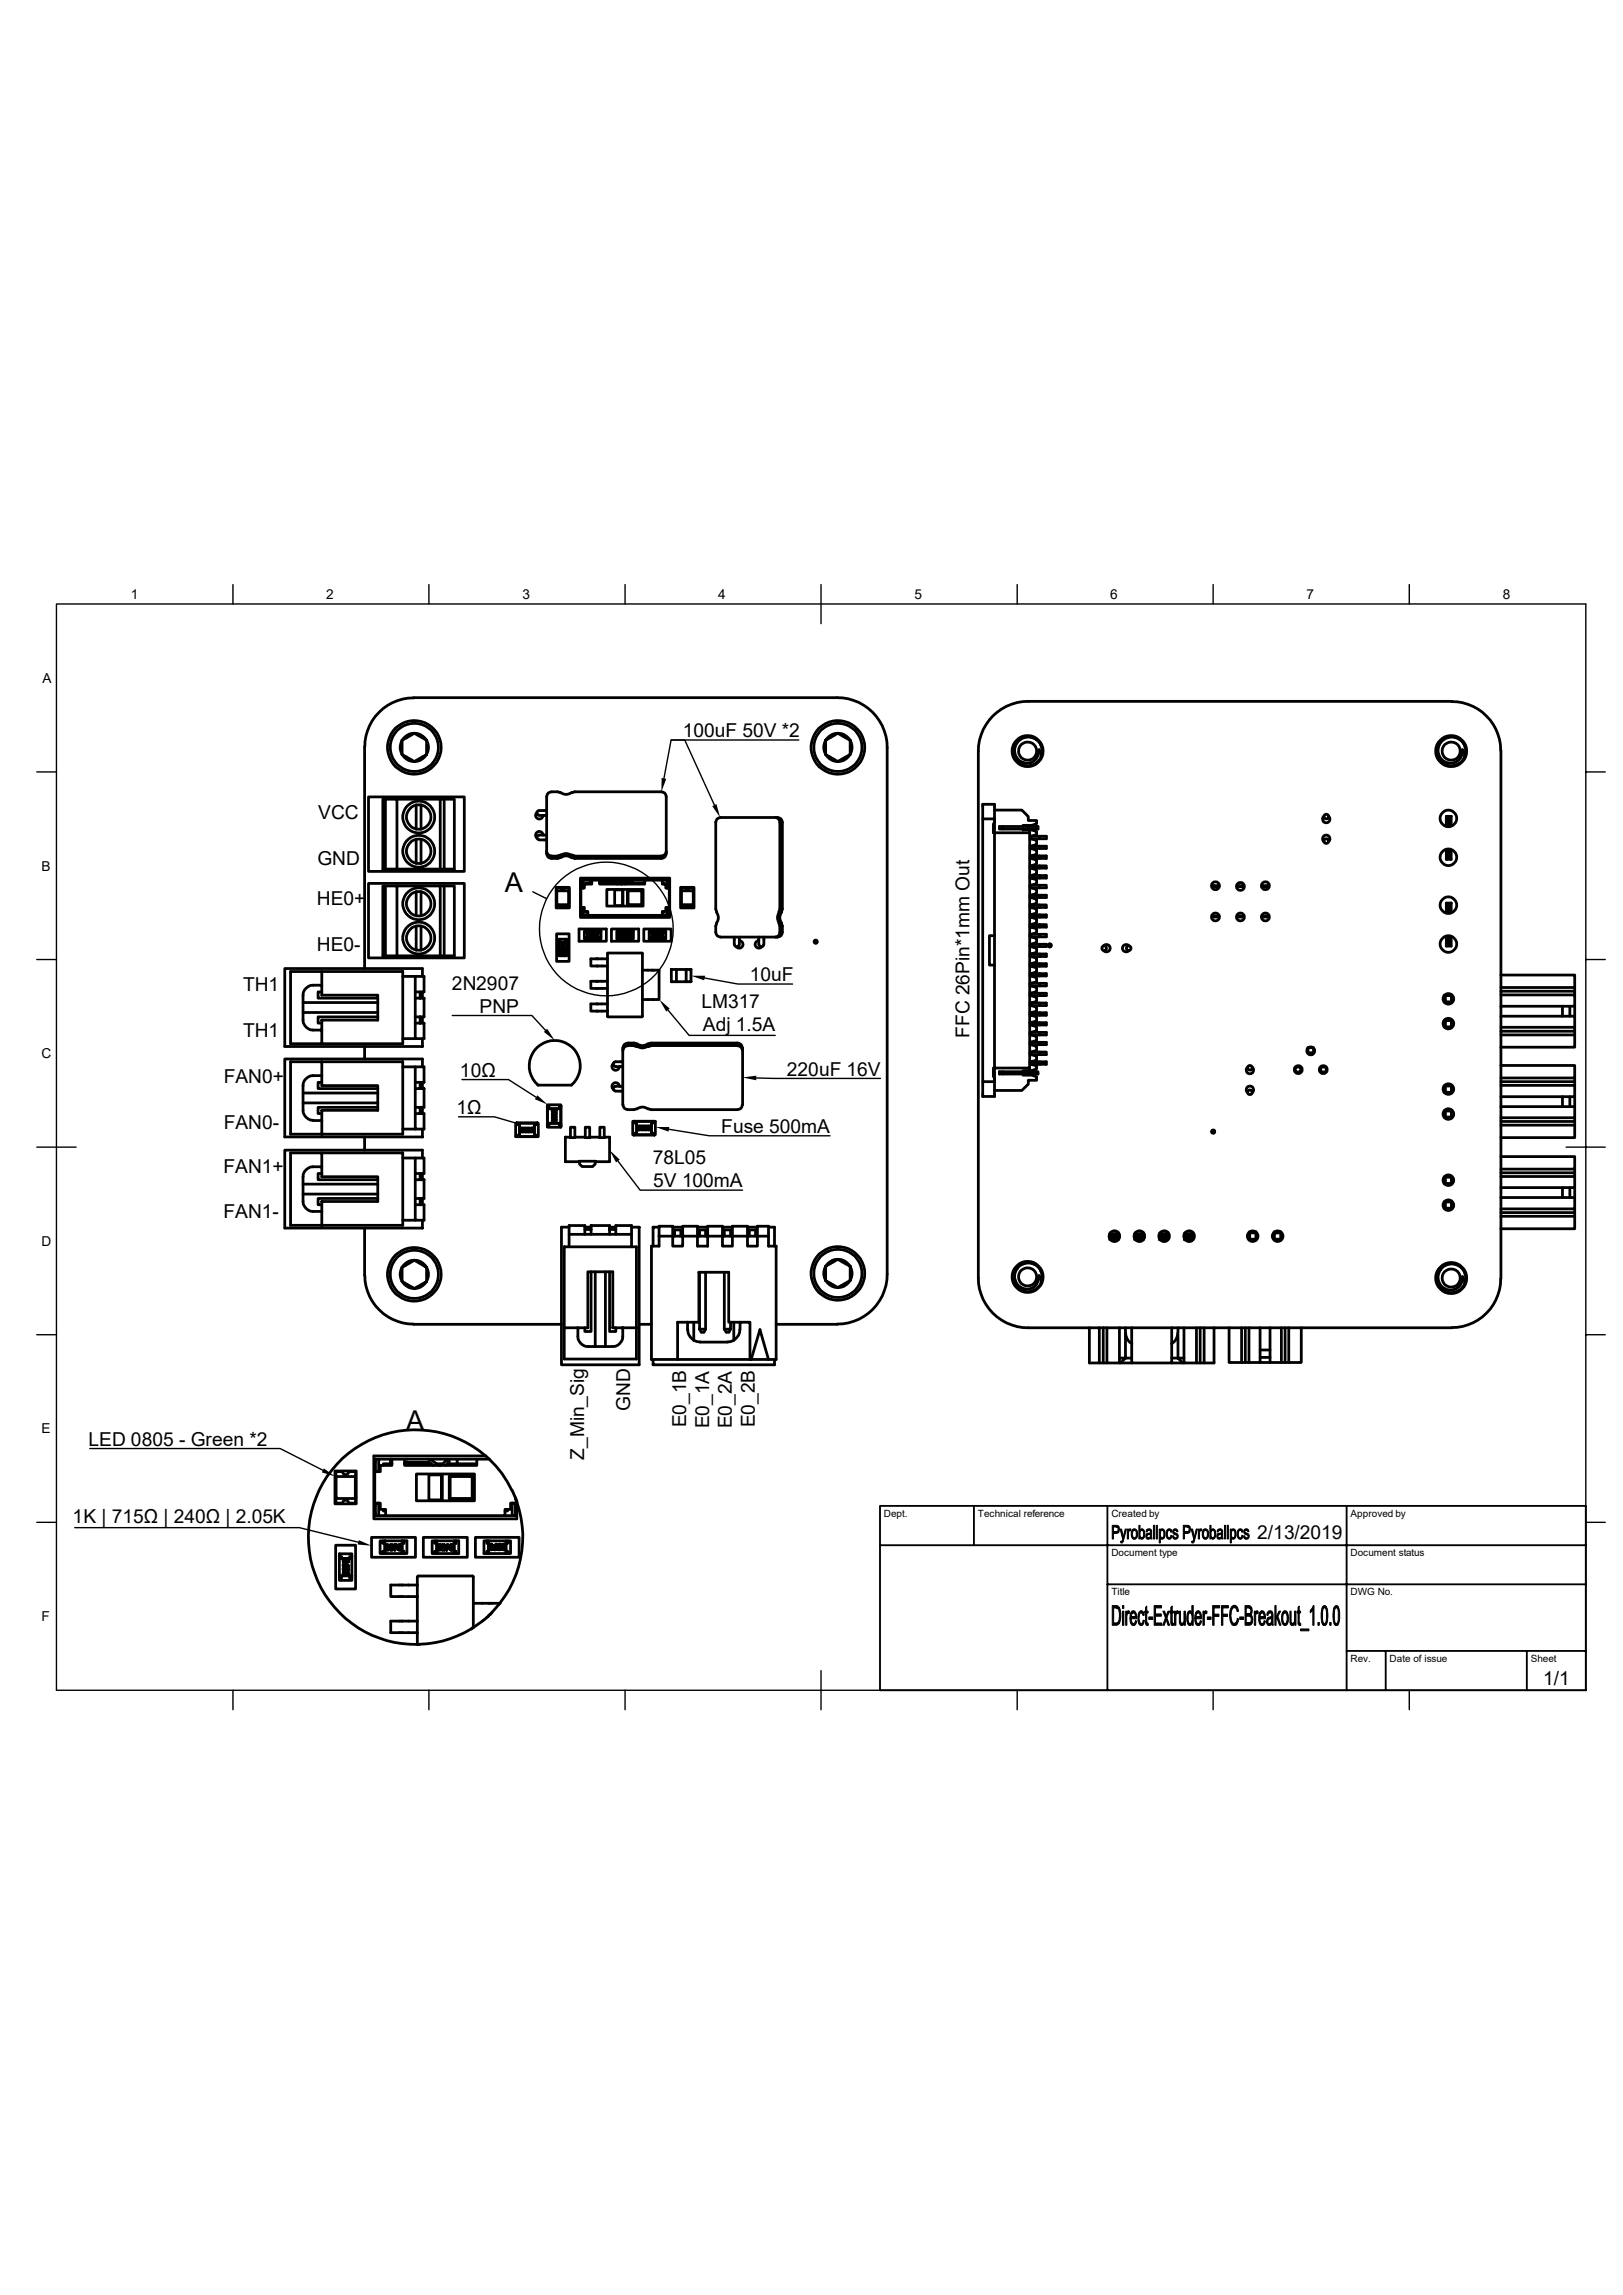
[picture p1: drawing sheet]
<svg xmlns="http://www.w3.org/2000/svg" width="297mm" height="420mm" viewBox="0 0 297 420" stroke-linecap="round" stroke-linejoin="round" font-family="sans-serif">
<defs><g id="words">
<g font-size="5">
<text x="92.4" y="163.2">A</text>
<text x="74.3" y="261.7">A</text>
</g>
<g font-size="3.5">
<text x="124.9" y="134.9">100uF 50V *2</text>
<text x="58.2" y="149.9">VCC</text>
<text x="58.1" y="158.2">GND</text>
<text x="58" y="165.6">HE0+</text>
<text x="58" y="174">HE0-</text>
<text x="137.2" y="179.6">10uF</text>
<text x="44.5" y="181.4">TH1</text>
<text x="82.7" y="181.1">2N2907</text>
<text x="87.8" y="185.3">PNP</text>
<text x="128.4" y="184.5">LM317</text>
<text x="44.5" y="189.8">TH1</text>
<text x="128.6" y="188.7">Adj 1.5A</text>
<text x="177.4" y="189.9" transform="rotate(-90 177.4 189.9)">FFC 26Pin*1mm Out</text>
<text x="84.2" y="197.1">10Ω</text>
<text x="144" y="196.9">220uF 16V</text>
<text x="40.9" y="198.2">FAN0+</text>
<text x="83.5" y="203.9">1Ω</text>
<text x="40.9" y="206.6">FAN0-</text>
<text x="132" y="207.3">Fuse 500mA</text>
<text x="40.9" y="214.6">FAN1+</text>
<text x="119.5" y="213.1">78L05</text>
<text x="119.5" y="217.3">5V 100mA</text>
<text x="40.9" y="223">FAN1-</text>
<text x="115.3" y="258.3" transform="rotate(-90 115.3 258.3)">GND</text>
<text x="125.6" y="261.2" transform="rotate(-90 125.6 261.2)">E0_1B</text>
<text x="129.8" y="261.4" transform="rotate(-90 129.8 261.4)">E0_1A</text>
<text x="133.9" y="261.4" transform="rotate(-90 133.9 261.4)">E0_2A</text>
<text x="138.1" y="261.2" transform="rotate(-90 138.1 261.2)">E0_2B</text>
<text x="16.2" y="264.6">LED 0805 - Green *2</text>
<text x="106.9" y="267.2" transform="rotate(-90 106.9 267.2)">Z_Min_Sig</text>
<text x="13.3" y="278.8">1K | 715Ω | 240Ω | 2.05K</text>
<text x="230.1" y="281.7">2/13/2019</text>
<text x="282.4" y="308.4">1/1</text>
</g>
<g font-size="2.5">
<text x="24" y="109.6">1</text>
<text x="59.7" y="109.6">2</text>
<text x="95.6" y="109.6">3</text>
<text x="131.4" y="109.6">4</text>
<text x="167.3" y="109.6">5</text>
<text x="203.2" y="109.6">6</text>
<text x="239.1" y="109.6">7</text>
<text x="275" y="109.6">8</text>
<text x="7.7" y="125">A</text>
<text x="7.6" y="159.3">B</text>
<text x="7.6" y="193.7">C</text>
<text x="7.6" y="228">D</text>
<text x="7.6" y="262.3">E</text>
<text x="7.6" y="296.6">F</text>
</g>
<g font-size="1.8">
<text x="161.8" y="277.6">Dept.</text>
<text x="178.9" y="277.6">Technical reference</text>
<text x="203.4" y="277.6">Created by</text>
<text x="247.1" y="277.6">Approved by</text>
<text x="203.4" y="284.8">Document type</text>
<text x="247.1" y="284.8">Document status</text>
<text x="203.4" y="292">Title</text>
<text x="247.1" y="292">DWG No.</text>
<text x="247.1" y="304.2">Rev.</text>
<text x="254.3" y="304.2">Date of issue</text>
<text x="280.1" y="304.2">Sheet</text>
</g>
</g></defs>
<g fill="none" stroke="#000" stroke-width=".51">
<path d="M66.7 136.7v40.6M73.6 138.1l2.2 1.3M73.6 135.5v2.6M73.6 138a2.62 2.62 0 0 0 2.2 1.4M73.6 135.5a2.56 2.56 0 0 0 0 2.5M75.7 127.7h77.5a9.1 9.1 0 0 1 9.1 9.1v96.4a9.1 9.1 0 0 1-9.1 9.1M75.7 127.7a9 9 0 0 0-8.9 9M75.8 134.2l-2.2 1.3M75.8 134.2l2.3 1.3M75.8 134.2a2.54 2.54 0 0 1 2.3 1.3M75.8 134.2a2.54 2.54 0 0 0-2.2 1.3M78.1 135.5v2.6"/>
<path d="M78.1 138.1l-2.3 1.3M78.1 138a2.62 2.62 0 0 1-2.3 1.4M78.1 135.5a2.56 2.56 0 0 1 0 2.5M151.1 138.1l2.2 1.3M151.1 135.5v2.6M151.1 138a2.62 2.62 0 0 0 2.2 1.4M151.1 135.5a2.56 2.56 0 0 0 0 2.5M153.3 134.2l-2.2 1.3M153.3 134.2l2.3 1.3M153.3 134.2a2.54 2.54 0 0 1 2.3 1.3M153.3 134.2a2.54 2.54 0 0 0-2.2 1.3M155.6 135.5v2.6"/>
<path d="M155.6 138.1l-2.3 1.3M155.6 138a2.62 2.62 0 0 1-2.3 1.4M155.6 135.5a2.56 2.56 0 0 1 0 2.5M190.1 137.2a2.28 2.28 0 0 1-1.3 2.3l-.5 .2-1-.1a2.4 2.4 0 0 1-1.6-1.9l.1-1.3 .7-.8a2.38 2.38 0 0 1 1.5-.7l1.4 .3 .8 .7 .3 .5-.8-1.1-.8-.4-1-.2-1.2 .4-.9 .8-.4 1.1v1l.4 1 1.1 .9 .7 .2h.9l1.1-.4 .6-.5 .3-.8M190.2 137.2l.3 .7v.5M190.5 136.4l.2 1.4-.2 .6M265.7 128.4h-77.5a9.1 9.1 0 0 0-9.2 9.1v96.3a9.1 9.1 0 0 0 9.2 9.2h77.5a9 9 0 0 0 8.9-9M265.7 128.4a9 9 0 0 1 8.9 8.9M268 136.4l-.5-.7-.7-.6-1-.2-.8 .1-.8 .4-.7 .6-.4 1.1 .2 1a2.19 2.19 0 0 0 1.8 1.6h.5a1.93 1.93 0 0 0 1.4-.7l.2-.2M268 136.4l-.5-.8-.8-.6-1-.3-1 .2-.6 .3-.7 .6-.5 .9-.1 1 .2 .6 .4 .8 .8 .7 .9 .3h.9l.9-.3 .7-.6 .5-.8M268 136.4l.2 1.4-.1 .6M268 136.4h.1"/>
<path d="M268.1 138.4l-.2-.7-.3-.5-.1 1.1-.3 .5M274.7 137.3v96.7M67.4 145.8h17.6v13.7h-17.6zM70.5 146.3h2.1v12.7M72.6 146.3h8v12.7M76.2 147.3v4.5M76.2 153.6v4.4M77 147.3v4.5M77 153.6v4.4M80.6 146.3h.7v12.7M81.3 146.3h1.8v12.7h-13v-12.7h.4v12.7M98.3 148.7a.68 .68 0 0 0 .1 1.1 .68 .68 0 0 0 1-.6"/>
<path d="M98.7 153.7h1.3M98.7 149.2h1.3M99.4 152.8a.68 .68 0 0 0-1-.6 .68 .68 0 0 0-.1 1.2M100 155.8a.87 .87 0 0 0 .9 .8M100 152.8h-1.3a.42 .42 0 0 0-.4 .4 .42 .42 0 0 0 .4 .5M100 148.3h-1.3a.42 .42 0 0 0-.4 .5 .42 .42 0 0 0 .4 .4M100.9 156.7h1.2M102.6 145.1a2.46 2.46 0 0 0-2.3 .1l-.3 .6v10.4a.87 .87 0 0 0 .9 .9h1.2l.5-.2M102.6 145a1.64 1.64 0 0 0 2 0M102.6 157a1.64 1.64 0 0 1 2 0M102.6 156.5a1.83 1.83 0 0 1 2 0M102.6 156.5l-.5 .1"/>
<path d="M104.6 145.1l.6-.2h15.8a.87 .87 0 0 1 .9 .9v10.4a.87 .87 0 0 1-.9 .9h-15.8l-.6-.2M104.6 156.5l.6 .1M105.2 156.7h15.8M121.9 155.8a.87 .87 0 0 1-.9 .8M141.9 149.6a.87 .87 0 0 1 .8 .9v15.9l-.2 .5M179.8 149.9v-2.7h2.2v5.2h-.2v-1.5M181.8 150.9l.2 .6M182 149.9h-2.2v48.1h2.2M182 148.3h5l1.2 1.1v.8h1.5v.5l-.9 .3h-1.6v.3M182 150.3l-.2 .6M182.9 151.3h7v.4h-7zM183.5 151.3v.4"/>
<path d="M187.2 151.7v.2h1.2M188.3 151.3v.4M188.4 151.9l1.3 .3v.5l-1.2 .3v.5l1.2 .3v.7l-1.2 .3v.5l1.2 .3v.7l-1.2 .3v.5l1.2 .3v.7l-1.2 .3v.5l1.2 .3v.7l-1.2 .3v.5l1.2 .3v.7l-1.2 .3v.5l1.2 .3v.7l-1.2 .3v.5l1.2 .3v.7l-1.2 .3v.5l1.2 .3v.7l-1.2 .2v.6l1.2 .3v.7l-1.2 .3v.5l1.2 .3v.7l-1.2 .2v.6l1.2 .2v.8l-1.2 .3v.5l1.2 .3v.7l-1.2 .2v.6l1.2 .2v.8l-1.2 .2v.6l1.2 .2v.7l-1.2 .3v.5l1.2 .3v.8l-1.2 .2v.6l1.2 .2v.7l-1.2 .3v.5l1.2 .3v.8l-1.2 .2v.6l1.2 .2v.7l-1.2 .3v.5l1.2 .3v.7l-1.2 .3v.5l1.2 .3v.7l-1.2 .3v.5l1.2 .3v.7l-1.2 .3v.5l1.2 .3v.7l-1.2 .3v.5l1.2 .3v.7l-1.2 .3v.5l1.2 .3v.5l-1.3 .3M188.4 151.9v43.6h-6.4v-43.1h6.4M188.5 158.5h3v.4h-3M188.5 156.6h3v.5h-1.3M188.5 153h3v.5h-3M188.5 154.9h3v.4h-1.3M189.7 151.3v.4M190.2 154.9v.4h-1.7M190.2 156.6v.5h-1.7M190.2 153v.5"/>
<path d="M190.2 158.5v.4M242.3 154.1a.69 .69 0 0 1-.1-1.1 .69 .69 0 0 1 1 0 .69 .69 0 0 1-.1 1.1M242.3 149.4a.69 .69 0 0 0-.1 1 .69 .69 0 0 0 1 0 .69 .69 0 0 0-.1-1M264.7 151h.9M264.7 149.4h.9M264.7 155.7h.9M265 156.9l.6 .4h-.9zM265 150.6v-.8l-.3-.4v1.6M265 156l-.3-.3v1.6M265 149.8h.2M265.2 156.9v-.9l.4-.3v1.6M265.2 156h-.2v.9"/>
<path d="M265.6 149.4v1.6l-.4-.4M265.6 149.4l-.4 .4v.8h-.2l-.3 .4M58.9 177.8h14.8v13.2h-20.5v-13.2h5.7v2.5M67.4 161.7h17.6v13.6h-17.6zM70.5 162.1h2.1v12.8M72.6 162.1h8v12.8M73.7 178.7h3.9v2.8h-1.6M76 178.7v11.4h1.6v-2.9h-1.6M76.2 163.2v4.4M76.2 169.5v4.4M77 163.2v4.4M77 169.5v4.4"/>
<path d="M77.3 178.7v-1.4h-25.2v14.2h25.2v-1.4M80.6 162.1h.7v12.8M81.3 162.1h1.8v12.8h-13v-12.8h.4v12.8M101.8 162.4h2.4v3.8h-2.4zM101.9 170.9h2.2v5h-2.2zM101.9 163h2.2v2.6h-2.2zM102.3 172.4h1.4v2h-1.4zM102.3 174.6h.2v-.2h.9v.2h.3v.3h-1.4zM102.3 172.2h.2v.2h.9v-.2h.3M102.3 172.4v-.5h1.4v.5M102.3 174.4v.2M102.6 162.5h-.7v3.6h.7"/>
<path d="M102.7 162.5l.2 .4 .4-.2v-.2h.8v3.6h-.8l-.2-.4-.4 .2v.2M102.7 172.6a.29 .29 0 0 1 .4-.1 .29 .29 0 0 1 .2 .3l-.5 .1zM102.7 173.1l.2-.1 .4 .3-.3-.2v.2l-.2 .1-.1-.2zM102.7 174l.2-.1-.2 .2 .1 .2h.2v-.2l.2 .2v-.4l.1 .1v.2l-.2 .1a.24 .24 0 0 1-.3 0 .24 .24 0 0 1-.1-.3zM102.7 173.5l.4-.1 .2 .2v.1l-.1 .2h-.4l-.1-.2zM102.7 173.6l.5-.1 .1 .2-.4 .1zM102.7 172.6h.5l.1 .2h-.5zM102.7 173.1h.1a.15 .15 0 0 1 .2 0 .15 .15 0 0 1 0 .2h-.3zM103.7 174.4v.2M106 170h5v2.3h-5zM106.2 160.7h16.4v7.2h-16.4zM106.3 162.5h.5"/>
<path d="M106.3 166.1h.5M106.4 161.1h.4v1.3h-.4zM106.4 161.3v6M106.7 162.4v.1M106.7 166.1h.1M106.8 166.1h.1v.7h.7v.7h13.6v-.7h.6v-.7h.2M106.8 166.1h-.4v1.4h1.2M106.8 161.1h1.3v.5M106.8 162.4v.1M106.8 166.1v1.4M106.9 170.4h.3v.3h.3v.9h-.3v.2h-.3zM107.2 171.8h.3"/>
<path d="M107.2 170.4h.3M107.3 166.8v.2h.3M107.5 170.4h1.9v1.4h-1.9zM107.5 170.9h.4v.1l-.1-.1h-.2v.2l.1 .1-.1 .2 .3-.1-.1 .2-.3-.1zM108 170.9l.2-.1 .2 .2-.1 .5-.3-.2zM108.1 170.9h.2v.5l-.3-.1zM108.1 161.6h-.8v.2M108.1 161.1h9.9M108.1 161.6h.2M108.3 161.6v.2h-1.4v.7h-.1M108.3 161.1v.5M108.5 170.9a.21 .21 0 0 1 .3 0 .21 .21 0 0 1 0 .3l-.3 .3 .2-.3h-.2z"/>
<path d="M108.5 170.9h.3v.2l-.2 .1zM109 170.9h.1a.3 .3 0 0 1 .3 .2 .3 .3 0 0 1-.3 .4l-.1-.1zM109.1 170.9h.1a.28 .28 0 0 1 .1 .3 .28 .28 0 0 1-.2 .2zM109.4 170.4h.6v1.4h-.4M109.4 171.8h.2M109.6 170.4v.3h-.2v.9h.2v.2M109.7 161.6v.2h8.3v-.7h3.2v.7h.6v.7h.2M109.7 161.4h2.7l.6 .4M109.7 161.6h3M109.7 161.1v.5M111 162.8h6.7v3h-6.7zM111.2 175.5h-3.1v1.3h3.1"/>
<path d="M111.2 179.6h-3.1v1.3h3.1M111.9 170h5v2.3h-5zM112.4 161.1l1.3 .7M112.5 162.9h1.5v2.8h-1.5zM112.9 170.4h.3v.3h.2v.9h-.2v.2h-.3zM113.2 171.8h.2M113.2 170.4h.2M113.4 170.4h2v1.4h-2zM113.4 161.6h.6M113.5 170.9h.3l.1 .1-.2-.1h-.2v.2l.2 .1-.2 .2 .3-.1-.1 .2-.2-.1zM113.8 161.8l.8-.7 .3 .2-.5 .5M113.9 162.9v2.8"/>
<path d="M114 170.9l.2-.1 .1 .2-.1 .5-.3-.2zM114 170.9h.3l-.1 .5-.2-.1zM114.4 170.9l.2-.1 .2 .2-.2 .5h-.1l.1-.3h-.2zM114.5 170.9a.15 .15 0 0 1 .2 0 .15 .15 0 0 1 0 .2l-.1 .1zM114.6 161.6h1.1M114.8 163l.1-.1zM114.8 165.6l.1 .1zM114.8 163v2.6M114.9 163h2.5v2.6h-2.5zM114.9 170.9h.1a.3 .3 0 0 1 .3 .2 .3 .3 0 0 1-.3 .4l-.1-.1zM114.9 162.9h2.5M114.9 165.7h2.5"/>
<path d="M115 170.9l.2 .1v.4l-.3-.1zM115.4 170.4h.5v1.4h-.3M115.4 171.8h.2M115.6 170.4v.3h-.2v.9h.2v.2M115.7 161.1v.5h2.3M117.4 165.7h.1M117.4 162.9l.1 .1zM117.5 163v2.6M117.6 177.5h3v5.4h-3M117.8 170h5v2.3h-5zM119.1 170.4v.3h.2v.9h-.2v.2M119.1 170.4h-.3v1.4h.5"/>
<path d="M119.1 170.4h.2M119.3 170.4h2v1.4h-2zM119.4 170.9l.1-.1 .3 .1-.1 .5h-.3zM119.5 170.9h.2l-.1 .5-.2-.2zM119.9 171.2l.2-.1 .1 .2-.2 .1zM120.1 170.8l-.1 .3h.2l.1 .2-.2 .2-.2-.3zM120.4 170.9h.3l-.1 .5-.2-.1zM120.4 170.8h.2l.2 .2-.2 .5-.2-.2zM120.9 170.8l.3 .1v.1a.21 .21 0 0 1-.1 .4 .21 .21 0 0 1-.3-.2l.1 .2 .3-.1-.2-.2 .2-.2h-.3zM121.2 161.6h.3v.2M121.2 161.1h1.1v1.3h-.3v-1.3M121.3 171.8h.2"/>
<path d="M121.3 170.4h.2M121.5 166.8v.2h-.3M121.5 170.4h.3v1.4h-.3v-.2h-.2v-.9h.2zM122 166.1h.3v1.4h-1.1M122 162.4v.1M122 166.1v1.4M122 162.5h.5M122 166.1h.5M122.1 162.4v.1M122.1 166.1h.1M122.3 161.3h.2v6h-.2M122.9 179.6h.1"/>
<path d="M122.9 177.4v.1M123.7 177.4v.1M123.7 179.6h.1M123.8 177.4h1.8v2.3h-1.8zM123.8 177.4h-.9v2.3h.9M124.5 162.4h2.5v3.8h-2.5zM124.7 163h2.2v2.6h-2.2zM124.7 162.5h.7l.3 .4 .3-.2 .1-.2h.8v3.6h-.8l-.2-.4-.4 .2-.1 .2h-.7zM125.6 177.4h.8v2.3h-.8M125.6 179.6h.1M125.6 177.4v.1M126.4 177.4v.1"/>
<path d="M126.4 179.6h.1M126.9 163.2h.1M131.1 166.9a1.64 1.64 0 0 1 0 2.1M131.1 169a2.46 2.46 0 0 0 .1 2.2l.7 .3h10.4a.87 .87 0 0 0 .9-.9v-1.1l-.2-.5M131.1 166.9l-.1-.5v-15.9a.87 .87 0 0 1 .9-.9h10.4a.87 .87 0 0 1 .9 .9v15.9l-.2 .5M134.4 171.5v1.3M134.4 172.8a.42 .42 0 0 0 .4 .5 .42 .42 0 0 0 .5-.5M135.3 172.2a.68 .68 0 0 1 .6 1 .68 .68 0 0 1-1.2 .1M135.3 171.5v1.3M138.9 172.2a.68 .68 0 0 0-.6 1 .68 .68 0 0 0 1.1 .1M138.9 171.5v1.3M139.8 171.5l-.1 1.3a.42 .42 0 0 1-.4 .5 .42 .42 0 0 1-.4-.5"/>
<path d="M142.5 169a2.46 2.46 0 0 1 0 2.2l-.6 .3M142.6 166.9a1.83 1.83 0 0 0 0 2.1M143 166.9a1.64 1.64 0 0 0 0 2.1M182 171.2h-.9v5.4h.9M188.5 162h3v.5h-3M188.5 165.6h3v.5h-3M188.5 169.2h3v.5h-3M188.5 171h3v.5h-1.3M188.5 160.2h3v.5h-1.3M188.5 163.8h3v.5h-1.3M188.5 167.4h3v.5h-1.3M188.5 172.8h3v.4h-1.3"/>
<path d="M188.5 174.6h3v.4h-3M188.5 176.4h3v.4h-1.3M188.5 178.2h3v.4h-1.3M188.5 180h3v.4h-1.3M190.2 180v.4h-1.7M190.2 178.2v.4h-1.7M190.2 176.4v.4h-1.7M190.2 160.2v.5h-1.7M190.2 163.8v.5h-1.7M190.2 167.4v.5h-1.7M190.2 172.8v.4h-1.7M190.2 171v.5h-1.7"/>
<path d="M190.2 162v.5M190.2 165.6v.5M190.2 169.2v.5M190.2 174.6v.4M201.9 173.1a.69 .69 0 0 1 1-.1 .69 .69 0 0 1 0 1 .69 .69 0 0 1-1-.1M206.6 173.1a.69 .69 0 0 0-1-.1 .69 .69 0 0 0 0 1 .69 .69 0 0 0 1-.1M222.2 167.8h-.2v-.2h.8v.2M222.2 167.6v.2h.9v-.2h-.3M222.2 162.1v.2M222.8 162.1h.3v.2h-1.1v-.2h.8v.2M226.7 167.8h-.3v-.2h.8v.2M226.7 167.6v.2h.8v-.2h-.3"/>
<path d="M226.7 162.1v.2M227.2 162.1h.3v.2h-1.1v-.2h.8v.2M231.2 167.8h-.3v-.2h.8v.2M231.2 167.6v.2h.8v-.2h-.3M231.2 162.1v.2M231.7 162.1h.3v.2h-1.1v-.2h.8v.2M264.7 171.5l.3 .4h.2M264.7 165.3l.3 .3v.9l-.3 .3M264.7 166.8h.9M265 172.8h.2l.4 .3h-.9zM265 171.9v.9M265 165.6h.2"/>
<path d="M265.2 172.8v-.9l.4-.4v1.6M265.6 171.5h-.9v1.6M265.6 165.3h-.9v1.5M265.6 165.3l-.4 .3v.9h-.2M265.6 165.3v1.5l-.4-.3M274.7 178.4h13.5v2.3h-13.5M55.5 185.3h13.6M55.5 183.5h13.6M58.9 181.5h-.7v1.2h10.9M58.9 180.3v1.8h10.2v4.6h-10.2v4.3M58.9 198.1h-.7v1.1h10.9M58.9 196.9v1.8h10.2v4.5h-10.2v4.4"/>
<path d="M58.9 194.3h14.8v13.3h-20.5v-13.3h5.7v2.6M58.9 180.3h-1.6a1.88 1.88 0 0 0-1.8 1.8v4.6a1.88 1.88 0 0 0 1.8 1.8h1.6M58.9 196.9h-1.6a1.88 1.88 0 0 0-1.8 1.8v4.5a1.88 1.88 0 0 0 1.8 1.8M66.7 191.5v2.3M69.1 186.1h-10.9v1.1h.7M73.7 190.1h2.3M73.7 195.2h3.9v2.9h-1.6M76 195.2v11.4h1.6v-2.8h-1.6M76 182.7h1.6v3.4h-1.6M76 199.2h1.6v3.5h-1.6M76.9 181.5v1.2M76.9 186.1v1.1"/>
<path d="M76.9 198.1v1.1M77.3 195.2v-1.4h-25.2v14.3h25.2v-1.5M77.3 181.5v1.2M77.3 186.1v1.1M77.3 198.1v1.1M98.4 198.6h6.2a4.7 4.7 0 0 0 .3-6.7 4.7 4.7 0 0 0-6.8 0 4.7 4.7 0 0 0 .4 6.7M111.2 183.7h-3.1v1.3h3.1M111.3 186.1v-11.7l6.3 .1-.1 11.6M111.3 186.1h6.2M112.2 194.6a.68 .68 0 0 0 .1 1.2 .68 .68 0 0 0 1-.6M112.6 199.7h1.4M112.6 195.2h1.4"/>
<path d="M113.3 198.8a.68 .68 0 0 0-1-.6 .68 .68 0 0 0-.1 1.1M114 198.8h-1.4a.42 .42 0 0 0-.4 .4 .42 .42 0 0 0 .4 .4M114 194.3h-1.4a.42 .42 0 0 0-.4 .4 .42 .42 0 0 0 .4 .5M114 191.8v.3M114 192.2v10M114.9 191.4a.87 .87 0 0 0-.9 .8M114.9 191.3h1.1M116 191.4l.5 .2M116.5 191.1a2.46 2.46 0 0 0-2.2 0l-.3 .7M116.5 191a1.64 1.64 0 0 0 2.1 0M116.5 191.5a1.83 1.83 0 0 0 2.1 0M118.6 191.1l.5-.2h15.9a.87 .87 0 0 1 .8 .9"/>
<path d="M119.1 191.3h15.9M119.1 191.4l-.5 .2M135 191.4a.87 .87 0 0 1 .8 .8M135.9 191.8v.3M135.9 192.2v10M181.8 196.9v-1.4h.2v5.2h-2.2v-2.7M181.8 196.9l.2 .6M182 196.3l-.2 .6M182.9 196.1h7v.5h-7zM183.5 196.1v.5M187.2 196.6v.2h1.6l.9 .3v.6h-1.5v.7l-1.2 1.2h-5M188.3 196.1v.5"/>
<path d="M188.4 195.9h-1.2v.2M188.4 195.5v.4M188.5 192.5h3v.5h-3M188.5 194.3h3v.5h-1.3M188.5 181.8h3v.4h-1.3M188.5 188.9h3v.5h-1.3M188.5 183.6h3v.4h-1.3M188.5 185.3h3v.5h-1.3M188.5 187.2h3v.4h-1.3M188.5 190.8h3v.4h-1.3M189.7 196.1v.5M190.2 190.8v.4h-1.7"/>
<path d="M190.2 188.9v.5h-1.7M190.2 187.2v.4h-1.7M190.2 185.3v.5h-1.7M190.2 183.6v.4h-1.7M190.2 181.8v.4h-1.7M190.2 194.3v.5h-1.7M190.2 192.5v.5M228.3 195.3a.69 .69 0 0 0-.1 1 .69 .69 0 0 0 1 0 .69 .69 0 0 0 0-1M228.3 200a.69 .69 0 0 1-.1-1 .69 .69 0 0 1 1 0 .69 .69 0 0 1 0 1M237 195.3h1v.9h-1zM239.4 191.7h1v1h-1zM239.4 191.8a.72 .72 0 0 0 0 1 .72 .72 0 0 0 1 0 .72 .72 0 0 0 0-1"/>
<path d="M239.4 191.8l.3-.2 .6 .2M241.7 195.3h1v.9h-1zM264.2 182.2h1.4v1.1h-1.1v-1.1M264.2 198.8h1.4v1.1h-1.1v-1.1M264.2 186.8h1.4v1.1h-1.4M264.2 183.3h.3M264.2 199.9h.3M264.5 186.8v1.1M274.7 181.4h13.5v.7M274.7 182.1h13.5v2.1h-13.5M274.7 186h13.5v2h-13.5M274.7 198h13.5v.6"/>
<path d="M274.7 195h13.5v2.3h-13.5M274.7 198.6h13.5v2.1h-13.5M274.7 189.4h13.5M285.9 184.2v1.8M287.3 184.2v1.8M288.2 188v.7h-13.5M288.2 189.4v2.2h-13.5M288.2 180.7v.7M288.2 184.2v1.8M288.2 188.7v.7M288.2 197.3v.7M55.5 201.8h13.6"/>
<path d="M55.5 200h13.6M55.5 218.5h13.6M55.5 216.7h13.6M57.3 205.1h1.6M58.9 214.8h-.7v1.1h10.9M58.9 213.5v1.9h10.2v4.5h-10.2v4.3M58.9 211h14.8v13.2h-20.5v-13.2h5.7v2.5M58.9 213.5h-1.6a1.88 1.88 0 0 0-1.8 1.9v4.5a1.88 1.88 0 0 0 1.8 1.8h1.6M66.7 208.1v2.4M69.1 202.7h-10.9v1.1h.7M69.1 219.3h-10.9v1.2h.7M73.7 211.9h3.9v2.9h-1.6"/>
<path d="M73.7 206.6h2.3M76 211.9v11.4h1.6v-2.8h-1.6M76 215.9h1.6v3.4h-1.6M76.9 202.7v1.1M76.9 214.8v1.1M76.9 219.3v1.2M77.3 211.9v-1.4h-25.2v14.2h25.2v-1.4M77.3 202.7v1.1M77.3 214.8v1.1M77.3 219.3v1.2M94.5 205.6h3.8M94.5 208h3.8"/>
<path d="M94.7 205.6v.2h.4v1.9h-.4v.3M94.7 205.6h-.3v2.4h.7M94.7 205.6h.4M95.1 205.6h2.7v2.4h-2.7zM95.4 206.5l.3-.1 .1 .2v.4l-.1 .2a.4 .4 0 0 1-.4-.3 .4 .4 0 0 1 .1-.4zM95.5 206.5h.2l.1 .2-.1 .4-.3-.2zM96 206.5h.4l-.1 .3 .1 .3-.2 .1-.3-.1 .2-.3zM96 206.5h.3v.1l-.2 .1zM96.1 206.8h.2l.1 .2-.3 .1zM96.5 206.5l.3-.1 .1 .1a.38 .38 0 0 1 .1 .4 .38 .38 0 0 1-.4 .3l-.1-.2zM96.6 206.5h.2l.1 .2-.1 .4-.3-.2zM97.2 206.4h.3l-.3 .1v.2l.3 .1v.3l-.2 .1-.3-.2 .3 .1 .2-.1-.1-.2h-.3z"/>
<path d="M97.8 205.8h.3v-.2h.4v2.4h-.4v-.3h-.3zM97.8 208h.3M97.8 205.6h.3M100.2 202.9h2.4v2.7h-2.4zM100.2 202.2h2.4v.3h-.2v.4h-1.9v-.4h-.3zM100.2 206h.3v-.4h1.9v.4h.2M100.2 202.5v.4M100.2 205.6v.4M100.2 202.4v3.8M101 203.2l.1 .3h.2v-.3h.3l.2 .3-.2 .1 .1-.1-.1-.3-.2 .1v.3l-.4-.1zM101.1 203.8l.5-.1 .2 .3-.1 .2h-.5l-.2-.2zM101.1 204.3h.2a.28 .28 0 0 1 .4 0 .28 .28 0 0 1 .1 .3l-.2 .2-.2-.2-.2 .1-.2-.1z"/>
<path d="M101.1 204.4h.2v.2h-.2zM101.1 205l.5-.1 .1 .2-.4 .1zM101.2 204.9l.4-.1 .2 .2-.1 .3h-.2a.32 .32 0 0 1-.5-.3zM101.2 203.8h.4l.1 .2-.4 .1-.2-.1zM101.5 204.3h.2l-.1 .4-.2-.1zM102.6 205.6v.7h-2.4v-.3M102.6 202.5v.4M102.6 202.4v3.8M104.4 206.3h.8v1.9h-.8zM104.4 208.1h-.9v4.5h2.5M105.2 208.1h1.9M106 212.5h2.9v.5l-.4 .5h-2l-.5-.5z"/>
<path d="M107.1 206.3h.8v1.9h-.8zM107.9 208.1h1.9M108.9 212.6h2.6M109.8 206.3h.8v1.9h-.8zM110.6 208.1h.9v4.5M114 202.2a.87 .87 0 0 0 .9 .9h1.1l.5-.2M115.8 205.2h.4v.3h.3v1.9h-.3v.2h-.4zM116 205.2h3.8M116 207.6h3.8M116.2 205.2h.3M116.2 207.6h.3M116.5 205.2h2.7v2.4h-2.7z"/>
<path d="M116.5 202.9a1.64 1.64 0 0 1 2.1 0M116.8 206.2l.3-.2 .2 .2-.3-.1-.2 .1 .1 .3 .3-.1-.1 .4h-.3l.3-.1v-.2l-.3-.1zM117.4 206.1l.2-.1 .2 .2-.1 .6h-.2l-.2-.2zM117.4 206.2a.27 .27 0 0 1 .4 .1 .27 .27 0 0 1-.1 .4h-.3zM117.9 206.2l.2-.2 .3 .2-.2 .6-.3-.1 .1-.2zM117.9 206.2l.3-.1 .1 .2-.3 .1zM118 206.5h.2l.1 .2h-.3zM118.5 206.2h.3a.34 .34 0 0 1-.2 .5zM118.5 206.1l.2-.1 .2 .2-.1 .6h-.2l-.2-.2zM119.2 205.2h.7v2.4h-.4M119.2 207.6h.3M119.5 205.2v.3h-.3v1.9h.3v.2"/>
<path d="M135.8 202.2a.87 .87 0 0 1-.8 .9h-15.9l-.5-.2M222.2 206.8v.5M264.2 215.4h1.4v1.2h-1.1v-1.2M264.2 203.3h1.4v1.1h-1.4M264.2 220h1.4v1.1h-1.4M264.2 216.6h.3M264.5 203.3v1.1M264.5 220v1.1M274.7 202.5h13.5v2.1h-13.5M274.7 214.6h13.5v.7M274.7 211.7h13.5v2.3h-13.5M274.7 215.3h13.5v2h-13.5"/>
<path d="M274.7 219.2h13.5v2h-13.5M274.7 205.9h13.5M285.9 200.7v1.8M285.9 217.3v1.9M287.3 200.7v1.8M287.3 217.3v1.9M288.2 204.6v.6h-13.5M288.2 205.9v2.3h-13.5M288.2 200.7v1.8M288.2 205.2v.7M288.2 214v.6M288.2 217.3v1.9"/>
<path d="M66.7 224.7v8.7M66.8 233.4a9 9 0 0 0 8.9 8.9M73.6 234.5l2.2 1.3 2.3-1.3M73.6 234.5a2.57 2.57 0 0 0 4.5 0M73.7 223.3h2.3M75.8 230.6l-2.2 1.3v2.6M75.8 230.6l2.3 1.3v2.6M75.8 230.6a2.56 2.56 0 0 1 2.3 3.9M75.8 230.6a2.56 2.56 0 0 0-2.2 3.9M104.1 225.9h11.5v-1.6h-2.9v1.6M104.1 224.6h-1.4v25.2h14.3v-25.2h-1.4M107 225.9v-1.6h-2.9v3.9"/>
<path d="M107 225h1.2M107 224.6h1.2M108.2 232.7v11h-1.2v-.7M108.2 225.9v-1.6h3.3v1.6M108.9 232.7v13.7M110.8 232.7v13.7M111.5 232.7v11h1.2v-.7M111.5 225h1.2M111.5 224.6h1.2M115.6 225.9v2.3M120.6 224.4h2.5v3.7h1.8v-3.7h2.7v3.7h1.9v-3.7h2.7v3.7h1.8v-3.7h2.8v3.7h1.8v-3.7h2v3.7h1.4v20.7h-22.8v-20.7h1.4zM120.6 224.6h-1.1v3.5"/>
<path d="M120.6 226.2h20M123.1 224.6h1.8M123.4 226.2v-1.1h1.2v1.1M127.6 224.6h1.9M128 226.2v-1.1h1.1v1.1M128 232.8v10.4M129.1 232.8v10.4M132.2 224.6h1.8M132.5 226.2v-1.1h1.2v1.1M132.5 232.8v10.4M136.8 224.6h1.8M137.1 226.2v-1.1h1.2v1.1"/>
<path d="M140.6 224.6h1.1v3.5M151.1 231.7v2.7l2.2 1.2M151.1 231.7a2.6 2.6 0 0 0 2.2 3.9M153.3 230.5l-2.2 1.2M153.3 230.5l2.3 1.2M153.3 230.5a2.54 2.54 0 0 1 2.3 1.2M153.3 230.5a2.54 2.54 0 0 0-2.2 1.2M155.6 231.7v2.7l-2.3 1.2M155.6 231.7a2.6 2.6 0 0 1-2.3 3.9M190.1 233.4a2.47 2.47 0 0 1-.5 1.7l-.5 .5a1.99 1.99 0 0 1-1.6 .2l-.6-.1-.5-.4-.6-.8-.1-1.2 .2-.8 .2-.4 .9-.7 .6-.2 .9-.1 1.2 .5 .5 .4 .3 .7-.4-.8-1-.7-.7-.2-.9 .1-1.1 .4-.4 .4-.4 .6-.2 .8v1l.3 .7a2.77 2.77 0 0 0 2 1.4h.7l.8-.3 1-.8 .3-.6v-.3l-.3-.9M190.5 232.7l.2 1.3-.2 .7M203.1 225.8v1.1h1.2"/>
<path d="M203.1 225.8h1.2v1.1M203.1 226.8a.98 .98 0 0 1 .6-1.5 .98 .98 0 0 1 1.2 1 .98 .98 0 0 1-1.4 .8l-.3-.2M203.1 225.8l.4 .3M203.5 226.1h.5v.5h-.5zM203.5 226.6l-.4 .3M204 226.6l.3 .3M204.3 225.8l-.3 .3M204.6 225.5v1.4h-.3M204.6 226.9h.1M207.7 226.8a.98 .98 0 0 1 .5-1.5 .98 .98 0 0 1 1.3 1 .98 .98 0 0 1-1.5 .8l-.2-.2M207.7 225.8l.3 .3M207.7 225.8h1.1"/>
<path d="M207.7 225.8v1.1M208 226.1h.5v.5h-.5zM208 226.6l-.3 .3M208.8 225.8v1.1h-1.1M208.8 225.8l-.3 .3M209.2 225.5v1.4h-.4l-.3-.3M209.2 226.9h.1M212.2 226.8a.98 .98 0 0 1 .6-1.5 .98 .98 0 0 1 1.2 1 .98 .98 0 0 1-1.4 .8l-.3-.2M212.2 225.8l.4 .3M212.2 225.8h1.2M212.2 225.8v1.1M212.6 226.1h.5v.5h-.5z"/>
<path d="M212.6 226.6l-.4 .3M213.4 225.8v1.1h-1.2M213.4 225.8l-.3 .3M213.7 225.5v1.4h-.3l-.3-.3M213.7 226.9h.1M216.8 226.8a.98 .98 0 0 1 .5-1.5 .98 .98 0 0 1 1.3 1 .98 .98 0 0 1-1.5 .8l-.2-.2M216.8 225.8l.3 .3M216.8 225.8v1.1M216.8 225.8h1.1M217.1 226.1h.5v.5h-.5zM217.1 226.6l-.3 .3M217.9 225.8l-.3 .3"/>
<path d="M217.9 225.8v1.1l-.3-.3M218.3 225.5v1.4h-1.5M218.3 226.9h.1M228.7 225.4v1.4h1.1v-1.4M228.7 225.6h1.1M233.2 225.4v.2M234.4 225.4v1.4h-1.2v-1.2h1.2M268 232.9l.2 1.3-.1 .7M268.1 234.9l-.2-.8-.3-.5-.1 1.1-.3 .5M268.1 234.9l-.3 .5-.6 .7-.8 .3-1.2 .2-.9-.3-.9-.8-.5-1.1v-1.1l.5-1 .7-.7 1.2-.4 .9 .1 1.1 .5 .7 1-.4-.6-.6-.5-.9-.3h-1l-.8 .3-.5 .4-.4 .6-.3 .9 .1 .6 .3 .8 .5 .6 .5 .3 .7 .2h.7l.7-.3 .6-.6M274.7 222.6h13.5M288.2 221.2v.7h-13.5"/>
<path d="M288.2 222.6v2.3h-13.5M288.2 221.9v.7M75.7 242.4h27M103.3 243v-14.8h13.2v20.5h-13.2v-5.7h2.4M105.7 243h1.9v-10.3h4.5v10.3h4.4M105.7 243v1.6a1.88 1.88 0 0 0 1.9 1.8h4.5a1.88 1.88 0 0 0 1.9-1.8v-1.6M117 242.4h2.2M119.5 248.8v1h22.2v-1M125.8 242v1.3M125.9 243.3a2.28 2.28 0 0 0 2.2 2.3M127 242v3.3M128 243.2l.3 .6h.5l.3-.6"/>
<path d="M128 243.2h1.1M128.1 245.6h5M132.5 243.2l.4 .6h.5l.3-.6M133.7 242v1.2h-1.2M134.3 242v3.3M135.4 243.3a2.28 2.28 0 0 1-2.3 2.3M135.4 243.3v-1.3h1.8v6.8M135.4 242h-2.1v-9.2h-5.4v9.2h-3.9v6.8M137.5 248.8l1.6-5.5 1.5 5.5M142 242.4h11.2M199.3 243v6.4h3.3M201.2 243v6.4"/>
<path d="M201.9 243v6.4M202.6 243v6.4h2.3v-6.4M204.9 248.5h1.1l-.9 .9M204.9 249.4h2.2M206 244.3v4.2h1.1M206 243v1M206 244a2.36 2.36 0 0 0 1.1 1.9M207.1 243v6.4h7.3v-6.4M214.4 248.5h2.3M214.4 249.4h2.3M215.5 244a2.36 2.36 0 0 1-1.1 1.9M215.6 244.3v4.2l.9 .9"/>
<path d="M215.6 243v1M216.7 243v6.4h2.2v-6.4M219.6 243v6.4M220.3 243v6.4M222.2 243v6.4h-3.3M224.9 243v6.3h2.3M227.2 249.3h.7M227.2 243v6.3M227.9 243v6.3h.7M228.6 243v6.3h2v-6.3M230.6 248.4h1.8M230.6 247.1h1.8"/>
<path d="M230.6 249.3h1.8M232.4 243v6.3h2.1v-6.3M235.2 243v6.3h-.7M235.2 249.3h.6M235.8 243v6.3h2.3v-6.3M61.3 269.2h3.9v6h-3.9zM61.5 270.2h3.5v4h-3.5zM61.5 273.9v1.2h1.2a.55 .55 0 0 1 .5-.6 .55 .55 0 0 1 .6 .6M61.5 273.9h.1M63.8 269.3a.55 .55 0 0 1-.6 .6 .55 .55 0 0 1-.5-.6h-1.2v4.6M63.8 269.3h1.3v4.6M65.1 273.9v1.2h-1.3"/>
<path d="M65.1 273.9h.1M68.6 269.3h.7M68.6 275.1h.7M68.7 267.5h-.1v9.4h.1M69.1 269.3h.1M69.1 275.1v.1M69.3 275.1h.3v1.1h1v1.2h21.8v-1.2h1v-1.1h.3M69.3 275.2h-.6v2.2h1.9M69.3 267h-.6v2.3h.6M69.3 275.1v2.3M70.1 268.2v-.3h1.4v-.9h-2.2v2.3M70.1 276.2v.3h.5"/>
<path d="M71.5 267h12.2M71.5 267.9h.2M71.7 267.9v.3h-2.1v1.1h-.3M71.7 267v.9M74 267.6h4.4l.9 .6M74 267.9h4.9M74 267v.9M76.2 269.7h10.6v5h-10.6zM78.4 267l.5 .2M78.5 269.9h2.4v4.6h-2.4zM78.9 267.2l1.4 1M79.9 267.9h1.1"/>
<path d="M80.8 269.9v4.6M80.8 268.1l-.2 .1M80.9 268.1l.9-1 .5 .4-.8 .7M81.8 267.9h1.9M82.2 274.2h.2v.2zM82.2 270.2v4M82.4 270v.2h-.2zM82.4 270.2h4v4h-4zM82.4 270h4M82.4 274.4h4M86.4 274.2h.1l-.1 .2zM86.4 270l.1 .2h-.1z"/>
<path d="M86.5 270.2v4M87.2 267h-3.5v.9h3.5M88.8 266.4a19.6 19.6 0 0 0-31.2 8.3 19.6 19.6 0 0 0 18.8 26.2v-12.4M88.9 266.4h-20.5v11.6h26.2v-3.2a19.6 19.6 0 0 1-3.1 18.6M88.9 266.4a19.7 19.7 0 0 1 4.8 6.4M89.5 267h-2.3v1.2h-13.2v-.3M92.4 277.4h1.3M92.9 276.2v.3h-.5M93.7 275.2h.6v2.2h-.6zM93.7 272.8l.7 1.6M93.7 275.1v.1M93.7 275.1h.7"/>
<path d="M93.9 275.1v.1M94.4 274.4v2.5h-.1M94.4 274.4l.2 .5M61.4 282.8h3.7v8h-3.7zM62.1 288.8h.4v-.4h1.5v.4h.4v.4h-2.3zM62.1 288.4v-3.2h2.3v3.2M62.1 284.9h.4v.3h1.5v-.3h.4M62.1 288.4h2.3M62.1 288.4v.4M62.8 287l.3-.1h.5a.33 .33 0 0 1 .2 .4 .33 .33 0 0 1-.3 .2l-.6-.1zM62.8 285.5l.8-.2a.35 .35 0 0 1 .2 .4 .35 .35 0 0 1-.4 .3l-.5-.1-.1-.1zM62.9 287.1l.5-.2 .3 .1v.3l-.2 .1h-.4l-.2-.1z"/>
<path d="M62.9 287.7l.2-.1-.2 .3 .1 .3h.2l.1-.3 .3 .3 .1-.3-.1-.2 .2 .3-.1 .2h-.4l-.1 .1h-.3l-.1-.2zM62.9 286.2l.3-.1 .6 .5-.4-.3v.3a.32 .32 0 0 1-.3 .2 .32 .32 0 0 1-.3-.2zM62.9 285.5l.6-.1 .2 .1v.3l-.3 .1h-.4l-.1-.2zM64.4 284.9v-.5h-2.3v.8M64.4 284.9v.3M64.4 288.4v.4M68 281.3h8v3.7h-8zM69.6 282h.5v.4h.3v1.5h-.3v.4h-.5zM70.1 282h4.4v2.3h-.5M70.1 284.3h.3M70.4 282v2.3h3.2v-2.3M70.5 282.8l.5-.1 .2 .1-.1 .2a.23 .23 0 0 0-.3-.2 .23 .23 0 0 0-.1 .3l.2 .1-.2 .2v.1l.1 .1 .4-.1-.2 .2h-.3l-.1-.1 .1-.3-.2-.3z"/>
<path d="M71.3 282.8l.4-.1 .2 .2v.6l-.2 .2h-.2l-.2-.2zM71.5 282.8h.3l.1 .3-.1 .4-.2 .1-.2-.2zM72.1 282.8l.4-.1 .2 .2-.1 .3-.3 .5h-.1l.3-.4-.4-.2zM72.2 282.8h.4l-.1 .4-.3-.1zM72.9 282.8l.4-.1a.72 .72 0 0 1 0 1h-.2l-.2-.2zM73 282.8l.2-.1 .2 .3v.4l-.2 .2-.3-.3zM73.6 284.3h.4M74 282v.4h-.4v1.5h.4v.4M76.4 290.1h-4.9v2.1h4.9M76.4 296.7h-4.9v2.1h4.9M76.4 288.5l.1-.1h10l.1 .1v9.4l2.8-2.2M77.5 281.3h8v3.7h-8z"/>
<path d="M79.1 282h.5v.4h.3v1.5h-.3v.4h-.5zM79.6 284.3h.3M79.6 282h.3M79.9 282h3.2v2.3h-3.2zM80.1 282.8l.4-.1 .2 .2-.4-.2-.2 .2v.2l.3 .1-.3 .2 .1 .2 .4-.1-.2 .2-.3-.2zM80.8 282.8l.2-.1h.2l.2 .1v.6l-.2 .3h-.2l-.2-.2zM81 282.8h.2l.2 .2-.1 .5-.2 .1-.2-.2zM81.7 282.7h.3l.2 .2-.1 .3-.4 .5 .3-.4-.4-.2zM82.4 282.8l.1-.1 .4 .1 .1 .7a.33 .33 0 0 1-.3 .2 .33 .33 0 0 1-.4-.2zM82.5 282.8l.2-.1a.52 .52 0 0 1 .1 .8l-.2 .1a.42 .42 0 0 1-.1-.7zM83.1 282h.8v2.3h-.8M83.4 282v.4h-.3v1.5h.3v.4"/>
<path d="M86.3 298.1a19.4 19.4 0 0 1-9.5 2.8M86.4 298l-.1 .1M86.6 293.4h4.9M86.6 297.8l-.2 .1M87 281.3h8v3.7h-8zM89.1 282v.4h.3v1.5h-.3v.4M89.1 282h-.5v2.3h4.3M89.1 282h.3M89.4 282h3.2v2.3M89.4 282v2.3M89.6 282.7l.3-.1 .3 .2v.6l-.2 .2h-.3l-.2-.2zM89.6 295.5l-.2 .2"/>
<path d="M89.7 282.7h.3l.1 .2v.5l-.2 .1-.3-.1zM90 295.1l-.4 .4M90.8 282.6l-.2 .4h.2a.31 .31 0 0 1 .2 .3 .31 .31 0 0 1-.2 .3h-.3l-.2-.1v-.3zM91.1 282.7l.4-.1 .2 .1v.6l-.2 .3-.4-.1zM91.2 282.8l.4-.1 .1 .6a.25 .25 0 0 1-.3 .2 .25 .25 0 0 1-.3-.2zM91.5 293.4l-1.5 1.7M91.9 282.7l.3-.1 .3 .1-.2 .3 .2 .2v.2l-.2 .2h-.4l-.1-.3 .3 .2h.3v-.3l-.3-.1 .3-.3-.4-.1-.1 .1zM92.6 282h.3M92.9 282h.5v2.3h-.5v-.4h-.3v-1.5h.3zM76.4 300.9h.2M76.6 300.9h.2"/>
<circle cx="75.8" cy="136.8" r="4.4"/>
<circle cx="75.8" cy="136.8" r="4.9"/>
<circle cx="153.3" cy="136.8" r="4.4"/>
<circle cx="153.3" cy="136.8" r="4.9"/>
<circle cx="188" cy="137.5" r="2.84"/>
<circle cx="188" cy="137.5" r="1.65"/>
<circle cx="265.6" cy="137.5" r="2.84"/>
<circle cx="265.6" cy="137.5" r="1.65"/>
<circle cx="76.6" cy="155.8" r="2.25"/>
<circle cx="76.6" cy="149.5" r="2.25"/>
<circle cx="76.6" cy="155.8" r="2.92"/>
<circle cx="76.6" cy="149.5" r="2.92"/>
<circle cx="242.7" cy="153.9" r=".43"/>
<circle cx="242.7" cy="149.4" r=".43"/>
<circle cx="265.1" cy="156.9" r="1.52"/>
<circle cx="265.1" cy="149.8" r="1.52"/>
<circle cx="76.6" cy="165.4" r="2.25"/>
<circle cx="76.6" cy="171.7" r="2.25"/>
<circle cx="76.6" cy="165.4" r="2.92"/>
<circle cx="76.6" cy="171.7" r="2.92"/>
<circle cx="149.3" cy="172.3" r=".3"/>
<circle cx="192.1" cy="173" r=".3"/>
<circle cx="202" cy="173.5" r=".43"/>
<circle cx="206.5" cy="173.5" r=".43"/>
<circle cx="222.4" cy="162.1" r=".72"/>
<circle cx="222.4" cy="167.8" r=".72"/>
<circle cx="227" cy="162.2" r=".72"/>
<circle cx="227" cy="167.8" r=".72"/>
<circle cx="231.6" cy="162.1" r=".72"/>
<circle cx="231.6" cy="167.8" r=".72"/>
<circle cx="265.1" cy="172.8" r="1.52"/>
<circle cx="265.1" cy="165.7" r="1.52"/>
<circle cx="228.7" cy="199.9" r=".43"/>
<circle cx="228.7" cy="195.4" r=".43"/>
<circle cx="237.6" cy="195.7" r=".72"/>
<circle cx="242.1" cy="195.7" r=".72"/>
<circle cx="265" cy="199.3" r=".98"/>
<circle cx="265" cy="182.8" r=".98"/>
<circle cx="265" cy="187.3" r=".98"/>
<circle cx="222" cy="207.1" r=".3"/>
<circle cx="265" cy="203.9" r=".98"/>
<circle cx="265" cy="216" r=".98"/>
<circle cx="75.8" cy="233.2" r="4.4"/>
<circle cx="75.8" cy="233.2" r="4.9"/>
<circle cx="153.3" cy="233" r="4.4"/>
<circle cx="153.3" cy="233" r="4.9"/>
<circle cx="188" cy="233.7" r="2.84"/>
<circle cx="188" cy="233.7" r="1.65"/>
<circle cx="229.2" cy="226.2" r=".98"/>
<circle cx="233.8" cy="226.2" r=".98"/>
<circle cx="265" cy="220.6" r=".98"/>
<circle cx="265.6" cy="233.9" r="2.84"/>
<circle cx="265.6" cy="233.9" r="1.65"/>
<circle cx="63.1" cy="286.4" r=".22"/>
<circle cx="81.9" cy="283" r=".22"/>
<circle cx="90.6" cy="283.3" r=".2"/>
</g>
<g fill="none" stroke="#000" stroke-width=".25">
<path d="M10.3 110.5h279.9v198.8h-279.9zM42.6 107v3.5M78.5 107v3.5M114.4 107v3.5M150.2 107v7.1M186.1 107v3.5M222 107v3.5M257.9 107v3.5M122.8 135.4h2.5l5.4 11.9M146.2 135.4h-23.4l-1.3 7.1M6.7 141.3h3.6M290.2 141.3h3.6"/>
<path d="M6.7 175.6h3.6M97.5 163.2l2.5 1.3M128.9 179l6.1 1.1h10M290.2 175.6h3.6M82.8 185.8h14.5l2.5 2.8M84.5 197.6h8.5l5.1 3.2M122.3 184.9l3.8 4.6h15.8M138.4 197.3l22.7 .1M6.7 209.9h7.2M83.9 204.4h6.6l3.9 1.1M113.1 212.5l4 5.3h18.8M122.4 206.7l7.4 1.2h22.1"/>
<path d="M286.6 209.9h7.2M6.7 244.3h3.6M290.2 244.3h3.6M6.7 278.6h3.6M13.7 279.6h41.1l10.8 2.6M16.4 265.1h34.9l7.8 4M290.2 278.6h3.6M42.6 309.3v3.6M78.5 309.3v3.6M114.4 309.3v3.6M150.2 305.7v7.2M186.1 309.3v3.6"/>
<path d="M222 309.3v3.6M257.9 309.3v3.6"/>
<circle cx="110.9" cy="170" r="12.2"/>
</g>
<path d="M161 275.6h129.2v33.7h-129.2zM178.2 275.6v7.2M202.6 275.6v33.7M246.4 275.6v33.7M161 282.8h129.2M202.6 289.9h87.6M246.4 302.1h43.8M253.6 302.1v7.2M279.4 302.1v7.2" fill="none" stroke="#000" stroke-width=".34"/>
<g fill="#000" stroke="#000" stroke-width=".18">
<path d="M203.5 279.1h.9l.4 .3h-1v.9l.9 .1-.2 .2h-.7v1h-.3z" fill-rule="evenodd"/>
<path d="M204.2 279.4h.6l.1 .6-.2 .4-.9-.1h.5l.3-.1v-.5l-.2-.3z" fill-rule="evenodd"/>
<path d="M205 279.8h.2l.4 1.5-.2 .3z" fill-rule="evenodd"/>
<path d="M205.9 279.8h.2l-.5 2.2-.4 .1 .2-.2z" fill-rule="evenodd"/>
<path d="M206.3 279.8h.2v.3h.2l-.2 .4v1.1h-.2z" fill-rule="evenodd"/>
<path d="M206.6 279.9l.3-.1v.4l-.4-.1z" fill-rule="evenodd"/>
<path d="M207.3 279.9l.4-.1 .4 .4 .1 .9-.5 .6h-.3l-.2-.3h.5l.2-.2v-1l-.3-.2h-.4z" fill-rule="evenodd"/>
<path d="M208.4 279.1h.2v.9h.3l-.3 .4v.7l.2 .3h-.2v.2h-.2z" fill-rule="evenodd"/>
<path d="M208.6 280l.3-.2 .3 .1a1.57 1.57 0 0 1 .2 1.5l-.4 .3-.4-.2 .4-.1a.93 .93 0 0 0 0-1.4z" fill-rule="evenodd"/>
<path d="M209.9 279.9l.5-.1 .3 .2 .1 1.6h-.2v-.2h-.3l.2-.2v-.4l-.7-.1 .2-.1a.35 .35 0 0 0 .4-.1 .35 .35 0 0 0 0-.4l-.6-.1z" fill-rule="evenodd"/>
<path d="M212.3 280h.4z" fill-rule="evenodd"/>
<path d="M212.1 279.8h.2v.3h.3l-.3 .3v.7l.3 .3-.3 .1v.9h-.2z" fill-rule="evenodd"/>
<path d="M212.5 279.8a.57 .57 0 0 1 .7 .6v.7l-.2 .4-.4 .2-.3-.2a.78 .78 0 0 0 .7-.6 .78 .78 0 0 0-.2-.8l-.5-.1z" fill-rule="evenodd"/>
<path d="M213.7 279.8h.4l.3 .2h-.5l-.2 .2-.1 .8 .3 .4h-.3l-.2-.3v-.6z" fill-rule="evenodd"/>
<path d="M214.7 279.9l.6-.1 .3 .5h-.3l-.2-.3h-.4z" fill-rule="evenodd"/>
<path d="M216.5 279.1h.9l.4 .3h-1.1v.9l1 .1-.2 .2h-.8v1h-.2z" fill-rule="evenodd"/>
<path d="M217.2 279.4h.6v.6l-.1 .4-1-.1h.6l.3-.1v-.5l-.2-.3z" fill-rule="evenodd"/>
<path d="M218 279.8h.2l.4 1.5-.2 .3z" fill-rule="evenodd"/>
<path d="M218.9 279.8h.2l-.5 2.2-.4 .1 .2-.2z" fill-rule="evenodd"/>
<path d="M219.3 279.8h.2v.3h.2l-.2 .4v1.1h-.2z" fill-rule="evenodd"/>
<path d="M219.6 279.9l.3-.1v.4l-.4-.1z" fill-rule="evenodd"/>
<path d="M220.3 279.9l.4-.1 .4 .4v.9l-.4 .6h-.3l-.2-.3h.5l.2-.2v-1l-.3-.2h-.4z" fill-rule="evenodd"/>
<path d="M221.4 279.1h.2v.9h.3l-.3 .4v.7l.2 .3h-.2v.2h-.2z" fill-rule="evenodd"/>
<path d="M221.8 279.8l.4 .1a1.57 1.57 0 0 1 .2 1.5l-.4 .3-.4-.2 .4-.1a.93 .93 0 0 0 0-1.4h-.4z" fill-rule="evenodd"/>
<path d="M222.9 279.9l.5-.1 .3 .2 .1 1.6h-.2v-.2h-.3l.2-.2v-.4l-.7-.1 .2-.1a.41 .41 0 0 0 .5-.4l-.2-.2h-.5z" fill-rule="evenodd"/>
<path d="M225.3 280h.4z" fill-rule="evenodd"/>
<path d="M225.1 279.8h.2v.3h.3l-.3 .3v.7l.3 .3-.3 .1v.9h-.2z" fill-rule="evenodd"/>
<path d="M225.3 280l.2-.2a.57 .57 0 0 1 .7 .6v.7l-.2 .4-.4 .2-.3-.2a.78 .78 0 0 0 .7-.6 .78 .78 0 0 0-.2-.8z" fill-rule="evenodd"/>
<path d="M226.5 280l.4-.2 .4 .2h-.4l-.2 .3-.1 .7 .3 .4h-.3l-.2-.3z" fill-rule="evenodd"/>
<path d="M227.7 279.9l.6-.1 .3 .5h-.3l-.2-.3h-.4z" fill-rule="evenodd"/>
<path d="M203.5 293.8l1 .1 .4 .3-1.1 .1v2.7h1.1l-.5 .4h-.9z" fill-rule="evenodd"/>
<path d="M204.2 294.3l.7-.1 .2 1-.2 1.7v.1h-.5l.2-.1a2.61 2.61 0 0 0 .1-2.3l-.2-.3z" fill-rule="evenodd"/>
<path d="M205.1 282.1h.4l-.3 .3h-.1z" fill-rule="evenodd"/>
<path d="M205.4 294.9h.3v2.5h-.3z" fill-rule="evenodd"/>
<path d="M205.4 293.8h.3v.5h-.3z" fill-rule="evenodd"/>
<path d="M206 294.9h.2v.3h.2l-.2 .5v1.7h-.2z" fill-rule="evenodd"/>
<path d="M206.3 294.9l.2-.1 .2 .1-.1 .4-.4-.1z" fill-rule="evenodd"/>
<path d="M206.9 295.1h.5a.65 .65 0 0 0-.4 .8h1v.3h-1l.1 .7 .3 .2h-.4l-.2-.4v-.7z" fill-rule="evenodd"/>
<path d="M207.1 280.1l.5-.1-.1 .1a.99 .99 0 0 0-.2 1.1l.3 .2h-.4l-.1-.2-.1-.7z" fill-rule="evenodd"/>
<path d="M207.1 294.9l.2-.1a.97 .97 0 0 1 .7 1.1h-1h.8l-.1-.4-.2-.4h-.5z" fill-rule="evenodd"/>
<path d="M207 297.1h.6l.2-.5 .2 .1-.1 .2a.53 .53 0 0 1-.7 .5z" fill-rule="evenodd"/>
<path d="M208.4 295l.5-.2 .4 .3a.72 .72 0 0 0-.9 .9l.1 .7 .3 .4h-.4l-.2-.5 .1-1.2z" fill-rule="evenodd"/>
<path d="M208.6 281.4h.4z" fill-rule="evenodd"/>
<path d="M208.4 297.1h.6l.2-.6h.2v.3a.52 .52 0 0 1-.4 .6 .52 .52 0 0 1-.6-.3z" fill-rule="evenodd"/>
<path d="M208.8 295.1h.5l.1 .5-.2 .1-.1-.4z" fill-rule="evenodd"/>
<path d="M209.8 280.1l.4-.1-.2 .2-.1 .2-.2-.1z" fill-rule="evenodd"/>
<path d="M209.8 293.9v1h.3v.3h-.3v1.5l.2 .4h-.4v-1.9h-.1v-.3h.1v-.7z" fill-rule="evenodd"/>
<path d="M209.8 280.8h.7h-.1a.36 .36 0 0 0-.4 .2 .36 .36 0 0 0 .1 .4l.4 .1-.3 .2-.3-.1-.2-.3z" fill-rule="evenodd"/>
<path d="M209.6 297.1h.5v.3a.36 .36 0 0 1-.5-.3z" fill-rule="evenodd"/>
<path d="M210.2 295.9h.7v.5h-.7z" fill-rule="evenodd"/>
<path d="M210.1 281.4h.5z" fill-rule="evenodd"/>
<path d="M211.1 279.1h.2v2.5h-.2z" fill-rule="evenodd"/>
<path d="M211.6 279.1h.2v2.5h-.2z" fill-rule="evenodd"/>
<path d="M211.2 293.8h1.4v.5h-1.1v1.1h1v.4h-1v1.2h1.1v.4h-1.4z" fill-rule="evenodd"/>
<path d="M212.8 294.9h.3l.9 2.5h-.3z" fill-rule="evenodd"/>
<path d="M213.3 296.1l.1 .3-.3 1h-.3z" fill-rule="evenodd"/>
<path d="M213.7 294.9h.3l-.5 1.2-.1-.4z" fill-rule="evenodd"/>
<path d="M213.6 281.4h.4l.2-.4h.3l-.2 .5-.2 .2h-.3z" fill-rule="evenodd"/>
<path d="M214 280h.4l.1 .4h-.3z" fill-rule="evenodd"/>
<path d="M214.2 294.2l.3-.3v1h.2v.3h-.2l.1 1.9-.4-.1v-1.8h-.1v-.3h.1z" fill-rule="evenodd"/>
<path d="M214.6 280.1l.5-.1-.2 .1a.41 .41 0 0 0 .4 .5l.3 .4-.1 .5-.3 .2h-.3l-.2-.3h.5a.37 .37 0 0 0 .1-.4 .37 .37 0 0 0-.4-.2l-.3-.3z" fill-rule="evenodd"/>
<path d="M214.3 297.1h.4l.1 .3h-.4z" fill-rule="evenodd"/>
<path d="M214.6 281.1h.2l.2 .3h-.3z" fill-rule="evenodd"/>
<path d="M214.9 294.9h.2v.3h.3l-.2 .5v1.7h-.3z" fill-rule="evenodd"/>
<path d="M215.3 294.8l.4 .1-.1 .4-.5-.1z" fill-rule="evenodd"/>
<path d="M215.8 294.9h.2l.1 2.1 .6 .1a.44 .44 0 0 1-.6 .4 .44 .44 0 0 1-.3-.6z" fill-rule="evenodd"/>
<path d="M216.3 297.1h.4z" fill-rule="evenodd"/>
<path d="M216.7 294.9h.2v2.5h-.2v-.3l-.2-.1 .2-.3z" fill-rule="evenodd"/>
<path d="M217.4 294.9l.4-.1 .3 .3-.5 .1-.2 .5v.9l.3 .5h-.4l-.1-.6v-1z" fill-rule="evenodd"/>
<path d="M217.3 297.1h.8a.4 .4 0 0 1-.3 .4 .4 .4 0 0 1-.5-.4z" fill-rule="evenodd"/>
<path d="M218.1 282.1h.4l-.3 .3h-.1z" fill-rule="evenodd"/>
<path d="M218.1 293.8h.3v3.6h-.3v-.3h-.2l.2-.6v-.9l-.3-.5h.3z" fill-rule="evenodd"/>
<path d="M218.8 295.1h.4a.65 .65 0 0 0-.3 .8h1v.3h-1l.1 .7 .2 .2h-.4l-.1-.4-.1-.7z" fill-rule="evenodd"/>
<path d="M219 294.9l.3-.1 .2 .1 .3 .5 .1 .5h-1h.7v-.4l-.3-.4h-.5z" fill-rule="evenodd"/>
<path d="M218.8 297.1h.6l.2-.5 .3 .1-.1 .2a.58 .58 0 0 1-.7 .6z" fill-rule="evenodd"/>
<path d="M220.1 280.1l.5-.1-.1 .1a.99 .99 0 0 0-.2 1.1l.3 .2h-.4l-.2-.2v-.7z" fill-rule="evenodd"/>
<path d="M220.1 294.9h.2v.3h.3l-.2 .5v1.7h-.3z" fill-rule="evenodd"/>
<path d="M220.4 294.9l.2-.1 .3 .1-.1 .4-.5-.1z" fill-rule="evenodd"/>
<path d="M220.9 295.9h.7v.5h-.7z" fill-rule="evenodd"/>
<path d="M221.6 281.4h.4z" fill-rule="evenodd"/>
<path d="M222.8 280.1l.4-.1-.2 .2-.1 .2-.2-.1z" fill-rule="evenodd"/>
<path d="M222.8 280.8h.7h-.1a.36 .36 0 0 0-.5 .2 .36 .36 0 0 0 .2 .4l.4 .1-.3 .2-.3-.1-.2-.3z" fill-rule="evenodd"/>
<path d="M221.9 293.8h1.3v.5h-1v1.1h.9v.4h-.9v1.6h-.3z" fill-rule="evenodd"/>
<path d="M223.1 281.4h.5z" fill-rule="evenodd"/>
<path d="M224.1 279.1h.2v2.5h-.2z" fill-rule="evenodd"/>
<path d="M224.6 279.1h.2v2.5h-.2z" fill-rule="evenodd"/>
<path d="M223.5 293.8h1.3v.5h-1v1.1h.8v.4h-.8v1.6h-.3z" fill-rule="evenodd"/>
<path d="M225.4 294a.5 .5 0 0 1 .7-.1l.3 .3h-.6a.88 .88 0 0 0-.5 .8l.1 1.5a.58 .58 0 0 0 .5 .6l.5 .1-.3 .3-.6-.1-.4-.9-.1-1.5z" fill-rule="evenodd"/>
<path d="M226.4 296.2l.3 .1-.3 .8h-.5l.4-.3z" fill-rule="evenodd"/>
<path d="M225.9 294.2h.5l.3 .7h-.3l-.1-.4z" fill-rule="evenodd"/>
<path d="M226.9 295.9h.6v.5h-.6z" fill-rule="evenodd"/>
<path d="M226.6 281.4h.4l.2-.4h.3l-.1 .3-.3 .4h-.3z" fill-rule="evenodd"/>
<path d="M227 280h.3l.2 .4h-.3z" fill-rule="evenodd"/>
<path d="M227.6 280.1l.5-.1-.2 .1a.41 .41 0 0 0 .4 .5l.3 .4-.1 .5-.3 .2h-.3l-.2-.3h.5a.37 .37 0 0 0 .1-.4 .37 .37 0 0 0-.4-.2l-.3-.3z" fill-rule="evenodd"/>
<path d="M227.6 281.1h.2l.2 .3h-.3z" fill-rule="evenodd"/>
<path d="M227.8 293.8l1.1 .1 .2 .4h-1.1v1.1h1l-.1 .1 .2 .3h-1.1v1.2l1.1 .1-.2 .3h-1.1z" fill-rule="evenodd"/>
<path d="M228.6 294.3h.5l.1 .6-.2 .5h-1h.6l.3-.3v-.5l-.2-.3z" fill-rule="evenodd"/>
<path d="M228.7 295.8h.5v.8l-.1 .5-1.1-.1h.7a.77 .77 0 0 0 0-1.2z" fill-rule="evenodd"/>
<path d="M229.5 294.9h.2v.3h.3l-.2 .4v1.8h-.3z" fill-rule="evenodd"/>
<path d="M229.9 294.9l.2-.1 .2 .1-.1 .4-.5-.1z" fill-rule="evenodd"/>
<path d="M230.5 295.1h.5a.65 .65 0 0 0-.4 .8h1v.3h-1.1l.2 .7 .3 .2h-.5l-.1-.3-.1-1.1z" fill-rule="evenodd"/>
<path d="M230.6 294.9a.55 .55 0 0 1 .7 0 .55 .55 0 0 1 .2 .5l.1 .5h-1h.8l-.2-.6-.1-.2h-.6z" fill-rule="evenodd"/>
<path d="M230.5 297.1h.6l.2-.5 .3 .1-.2 .5-.3 .3a.48 .48 0 0 1-.6-.4z" fill-rule="evenodd"/>
<path d="M231.9 295.1h.5l-.2 .1-.2 .5-.2-.1z" fill-rule="evenodd"/>
<path d="M231.9 296.2l.8-.1-.7 .4 .2 .6 .5 .1-.3 .3a.52 .52 0 0 1-.6-.5z" fill-rule="evenodd"/>
<path d="M232 294.9a.56 .56 0 0 1 .7 0 .56 .56 0 0 1 .3 .6v1.9h-.2l-.1-.3h-.2l.2-.4v-.6h-.7l.7-.3v-.5l-.2-.2h-.6z" fill-rule="evenodd"/>
<path d="M232.3 297.1h.4z" fill-rule="evenodd"/>
<path d="M233.3 293.8h.2v2.1l.2 .2-.2 .3v1h-.2z" fill-rule="evenodd"/>
<path d="M234.1 294.9h.3l-.6 .9 .6 1.6h-.3l-.6-1.5z" fill-rule="evenodd"/>
<path d="M234.7 295.2l.5-.1-.3 .2-.2 .6 .1 .8 .3 .4h-.4l-.1-.3-.1-1.1z" fill-rule="evenodd"/>
<path d="M234.9 294.9a.59 .59 0 0 1 .6 0 .59 .59 0 0 1 .2 .6v1.4a.66 .66 0 0 1-.7 .6l-.3-.4h.5l.2-.2 .1-1.1-.2-.6-.6-.1z" fill-rule="evenodd"/>
<path d="M236.1 294.9h.2v2l.2 .2h.4a.44 .44 0 0 1-.5 .4 .44 .44 0 0 1-.3-.6z" fill-rule="evenodd"/>
<path d="M236.6 297.1h.3z" fill-rule="evenodd"/>
<path d="M236.9 294.9h.3v2.5h-.3v-.3l-.2-.1 .2-.3z" fill-rule="evenodd"/>
<path d="M237.7 293.9v1h.3v.3h-.3v1.6l.2 .3h-.4v-1.9h-.1v-.3h.1v-.7z" fill-rule="evenodd"/>
<path d="M237.5 297.1h.5v.3a.35 .35 0 0 1-.3 0 .35 .35 0 0 1-.2-.3z" fill-rule="evenodd"/>
<path d="M238 298.1h1.5v.4h-1.5z" fill-rule="evenodd"/>
<path d="M239.8 294.7l.1-.1h.3l-.4 .5z" fill-rule="evenodd"/>
<path d="M240.3 293.8h.2v3.6h-.3v-2.8h-.3z" fill-rule="evenodd"/>
<path d="M241.2 296.9h.2v.5h-.2z" fill-rule="evenodd"/>
<path d="M242 294.2h.4l-.3 .3-.1 .4v1.6l.4 .6-.4 .1-.2-1v-1.1z" fill-rule="evenodd"/>
<path d="M242 294a.48 .48 0 0 1 .6-.1 .48 .48 0 0 1 .3 .5l.1 .9-.1 1.5a.6 .6 0 0 1-.7 .6l-.2-.2 .5-.1 .2-.4v-1.8a.65 .65 0 0 0-.7-.7z" fill-rule="evenodd"/>
<path d="M243.3 296.9h.3v.5h-.3z" fill-rule="evenodd"/>
<path d="M244.1 294.2h.5l-.3 .2-.1 .6v1.6l.1 .4 .3 .1-.5 .1-.2-1.1 .1-1.3z" fill-rule="evenodd"/>
<path d="M244.2 294l.2-.2a.75 .75 0 0 1 .7 .9v2.1a.64 .64 0 0 1-.7 .7l-.3-.3 .5-.1 .3-.6v-1.6l-.1-.5-.2-.2h-.5z" fill-rule="evenodd"/>
</g>
<path d="M121.1 142.4l.8 .1-.9 2.4zM130.3 147.5l.8-.3 .7 2.4zM126.4 178.6h2.6l-.1 .8zM100.1 188.3l1.4 2.1-2-1.6zM120.6 182.9l2 1.7-.7 .5zM135.9 197.2l2.5-.3v.8zM98.3 200.4l1.9 1.7-2.3-.9zM111.5 210.5l1.9 1.7-.7 .5zM119.9 206.2h2.6l-.2 .9zM59.3 268.7l2 1.5-2.4-.7zM65.7 281.9l2.3 1-2.6-.2z" fill="#000"/>
<use href="#words"/>
</svg>
